VERSION 5.7 ;
  NOWIREEXTENSIONATPIN ON ;
  DIVIDERCHAR "/" ;
  BUSBITCHARS "[]" ;
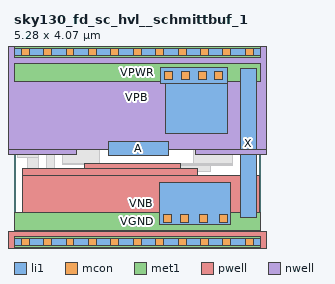
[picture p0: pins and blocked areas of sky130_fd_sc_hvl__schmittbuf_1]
MACRO sky130_fd_sc_hvl__schmittbuf_1
  CLASS BLOCK ;
  FOREIGN sky130_fd_sc_hvl__schmittbuf_1 ;
  ORIGIN 0.000 0.000 ;
  SIZE 5.280 BY 4.070 ;
  PIN A
    ANTENNAGATEAREA 1.170000 ;
    PORT
      LAYER li1 ;
        RECT 2.015 1.855 3.305 2.150 ;
    END
  END A
  PIN VGND
    USE GROUND ;
    PORT
      LAYER li1 ;
        RECT 3.120 0.375 4.630 1.285 ;
      LAYER mcon ;
        RECT 3.210 0.425 3.380 0.595 ;
        RECT 3.570 0.425 3.740 0.595 ;
        RECT 3.980 0.425 4.150 0.595 ;
        RECT 4.410 0.425 4.580 0.595 ;
      LAYER met1 ;
        RECT 0.000 0.255 5.280 0.625 ;
    END
  END VGND
  PIN VNB
    ANTENNADIFFAREA 0.897600 ;
    PORT
      LAYER pwell ;
        RECT 1.520 1.585 3.575 1.675 ;
        RECT 0.190 1.575 3.575 1.585 ;
        RECT 0.190 1.415 3.940 1.575 ;
        RECT 0.190 0.215 5.260 1.415 ;
        RECT -0.130 -0.215 5.410 0.215 ;
      LAYER li1 ;
        RECT 0.000 -0.085 5.280 0.085 ;
      LAYER mcon ;
        RECT 0.155 -0.085 0.325 0.085 ;
        RECT 0.635 -0.085 0.805 0.085 ;
        RECT 1.115 -0.085 1.285 0.085 ;
        RECT 1.595 -0.085 1.765 0.085 ;
        RECT 2.075 -0.085 2.245 0.085 ;
        RECT 2.555 -0.085 2.725 0.085 ;
        RECT 3.035 -0.085 3.205 0.085 ;
        RECT 3.515 -0.085 3.685 0.085 ;
        RECT 3.995 -0.085 4.165 0.085 ;
        RECT 4.475 -0.085 4.645 0.085 ;
        RECT 4.955 -0.085 5.125 0.085 ;
      LAYER met1 ;
        RECT 0.000 -0.115 5.280 0.115 ;
    END
  END VNB
  PIN VPB
    ANTENNADIFFAREA 0.897600 ;
    PORT
      LAYER nwell ;
        RECT -0.330 1.975 5.610 4.485 ;
        RECT -0.330 1.885 1.340 1.975 ;
        RECT 3.885 1.885 5.610 1.975 ;
      LAYER li1 ;
        RECT 0.000 3.985 5.280 4.155 ;
      LAYER mcon ;
        RECT 0.155 3.985 0.325 4.155 ;
        RECT 0.635 3.985 0.805 4.155 ;
        RECT 1.115 3.985 1.285 4.155 ;
        RECT 1.595 3.985 1.765 4.155 ;
        RECT 2.075 3.985 2.245 4.155 ;
        RECT 2.555 3.985 2.725 4.155 ;
        RECT 3.035 3.985 3.205 4.155 ;
        RECT 3.515 3.985 3.685 4.155 ;
        RECT 3.995 3.985 4.165 4.155 ;
        RECT 4.475 3.985 4.645 4.155 ;
        RECT 4.955 3.985 5.125 4.155 ;
      LAYER met1 ;
        RECT 0.000 3.955 5.280 4.185 ;
    END
  END VPB
  PIN VPWR
    USE POWER ;
    PORT
      LAYER li1 ;
        RECT 3.130 3.405 4.570 3.735 ;
        RECT 3.235 2.320 4.570 3.405 ;
      LAYER mcon ;
        RECT 3.225 3.475 3.395 3.645 ;
        RECT 3.585 3.475 3.755 3.645 ;
        RECT 3.945 3.475 4.115 3.645 ;
        RECT 4.305 3.475 4.475 3.645 ;
      LAYER met1 ;
        RECT 0.000 3.445 5.280 3.815 ;
    END
  END VPWR
  PIN X
    ANTENNADIFFAREA 0.596250 ;
    PORT
      LAYER li1 ;
        RECT 4.860 0.515 5.195 3.715 ;
    END
  END X
  OBS
      LAYER li1 ;
        RECT 0.740 3.655 1.030 3.735 ;
        RECT 0.085 3.485 1.030 3.655 ;
        RECT 0.085 1.975 0.255 3.485 ;
        RECT 0.740 3.405 1.030 3.485 ;
        RECT 1.200 3.235 2.790 3.405 ;
        RECT 0.430 2.335 0.680 3.085 ;
        RECT 0.430 2.165 0.875 2.335 ;
        RECT 1.200 2.295 1.460 3.235 ;
        RECT 1.655 2.330 2.010 3.065 ;
        RECT 0.085 1.805 0.530 1.975 ;
        RECT 0.280 1.090 0.530 1.805 ;
        RECT 0.705 0.795 0.875 2.165 ;
        RECT 1.655 1.985 1.835 2.330 ;
        RECT 2.460 2.320 2.790 3.235 ;
        RECT 1.045 1.685 1.835 1.985 ;
        RECT 3.855 1.685 4.690 2.055 ;
        RECT 1.045 1.655 4.690 1.685 ;
        RECT 1.600 1.645 4.690 1.655 ;
        RECT 1.600 1.505 4.210 1.645 ;
        RECT 1.060 1.145 1.390 1.410 ;
        RECT 1.600 1.315 1.940 1.505 ;
        RECT 2.390 1.145 2.720 1.335 ;
        RECT 1.060 0.975 2.720 1.145 ;
        RECT 0.705 0.570 2.010 0.795 ;
  END
END sky130_fd_sc_hvl__schmittbuf_1
END LIBRARY

